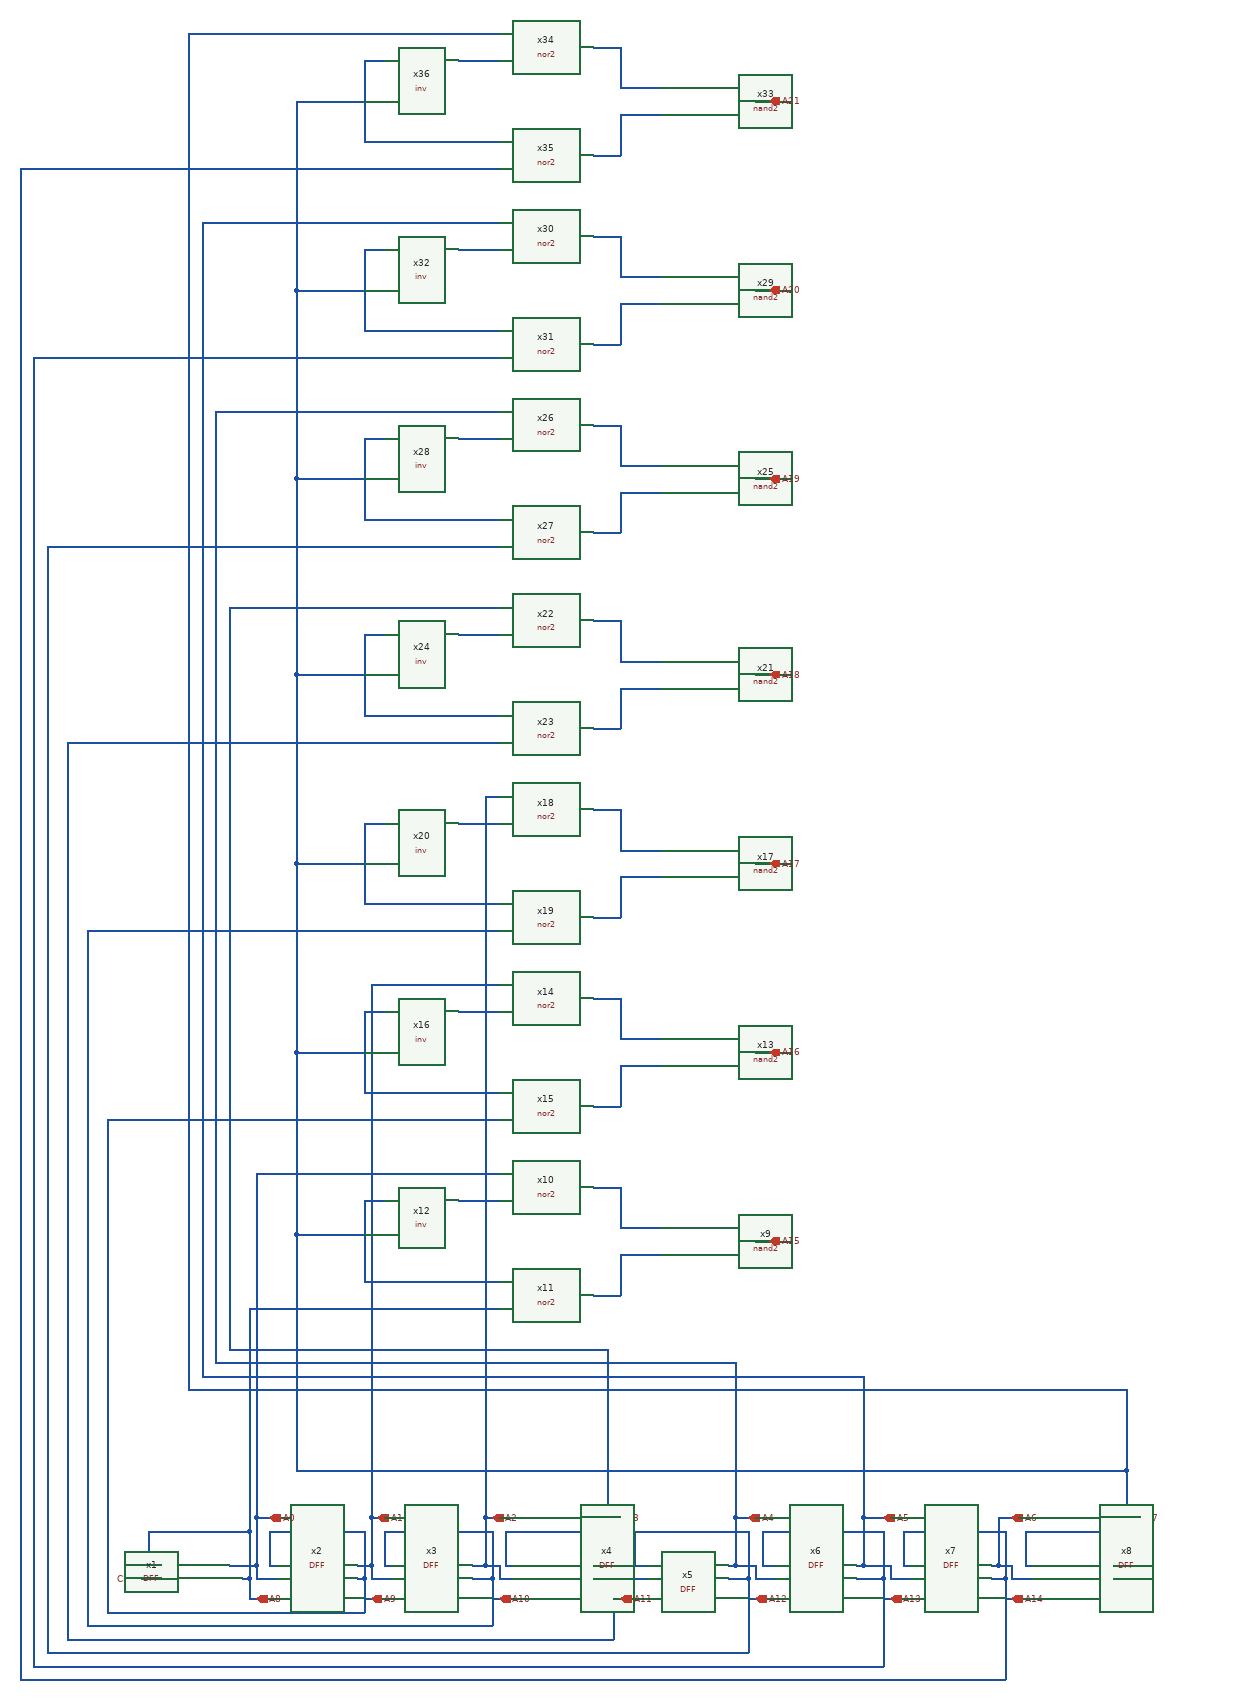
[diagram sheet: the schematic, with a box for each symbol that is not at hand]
v {xschem version=3.1.0 file_version=1.2 }
G {}
K {}
V {}
S {}
E {}
N 20 40 60 40 {
lab=A0}
N 60 -30 60 40 {
lab=A0}
N -80 -10 50 -10 {
lab=A8}
N 40 60 50 60 {
lab=A8}
N -100 40 -80 40 {
lab=A8}
N -100 -10 -100 40 {
lab=A8}
N -100 -10 -80 -10 {
lab=A8}
N 50 -10 50 60 {
lab=A8}
N 60 60 70 60 {
lab=A0}
N 60 40 60 60 {
lab=A0}
N 60 -30 90 -30 {
lab=A0}
N 70 60 90 60 {
lab=A0}
N 210 60 220 60 {
lab=A9}
N 220 -10 220 60 {
lab=A9}
N 80 -10 220 -10 {
lab=A9}
N 80 -10 80 40 {
lab=A9}
N 80 40 90 40 {
lab=A9}
N 210 40 230 40 {
lab=A1}
N 230 -30 230 40 {
lab=A1}
N 230 -30 250 -30 {
lab=A1}
N 230 40 230 60 {
lab=A1}
N 230 60 260 60 {
lab=A1}
N 250 40 260 40 {
lab=A10}
N 250 -10 250 40 {
lab=A10}
N 250 -10 410 -10 {
lab=A10}
N 410 -10 410 60 {
lab=A10}
N 380 60 410 60 {
lab=A10}
N 380 40 400 40 {
lab=A2}
N 400 -30 400 40 {
lab=A2}
N 400 -30 420 -30 {
lab=A2}
N 400 40 420 40 {
lab=A2}
N 420 40 420 60 {
lab=A2}
N 420 60 440 60 {
lab=A2}
N 430 40 440 40 {
lab=A11}
N 430 -10 430 40 {
lab=A11}
N 430 -10 590 -10 {
lab=A11}
N 590 -10 590 60 {
lab=A11}
N 560 60 590 60 {
lab=A11}
N 560 40 580 40 {
lab=A3}
N 580 -30 580 40 {
lab=A3}
N 580 -30 600 -30 {
lab=A3}
N 580 40 600 40 {
lab=A3}
N 600 40 600 60 {
lab=A3}
N 600 60 640 60 {
lab=A3}
N 620 40 640 40 {
lab=A12}
N 620 -10 620 40 {
lab=A12}
N 620 -10 790 -10 {
lab=A12}
N 790 -10 790 60 {
lab=A12}
N 760 60 790 60 {
lab=A12}
N 760 40 770 40 {
lab=A4}
N 770 -30 770 40 {
lab=A4}
N 770 -30 800 -30 {
lab=A4}
N 770 40 800 40 {
lab=A4}
N 800 40 800 60 {
lab=A4}
N 800 60 830 60 {
lab=A4}
N 810 40 830 40 {
lab=A13}
N 810 -10 810 40 {
lab=A13}
N 810 -10 990 -10 {
lab=A13}
N 990 -10 990 60 {
lab=A13}
N 950 60 990 60 {
lab=A13}
N 950 40 960 40 {
lab=A5}
N 960 -30 960 40 {
lab=A5}
N 960 -30 1000 -30 {
lab=A5}
N 960 40 1000 40 {
lab=A5}
N 1000 40 1000 60 {
lab=A5}
N 1000 60 1030 60 {
lab=A5}
N 1020 40 1030 40 {
lab=A14}
N 1020 -10 1020 40 {
lab=A14}
N 1020 -10 1170 -10 {
lab=A14}
N 1170 -10 1170 60 {
lab=A14}
N 1150 60 1170 60 {
lab=A14}
N 1150 40 1160 40 {
lab=A6}
N 1160 -30 1160 40 {
lab=A6}
N 1160 -30 1190 -30 {
lab=A6}
N 1160 40 1180 40 {
lab=A6}
N 1180 40 1180 60 {
lab=A6}
N 1180 60 1210 60 {
lab=A6}
N 1200 40 1210 40 {
lab=#net1}
N 1200 -10 1200 40 {
lab=#net1}
N 1200 -10 1360 -10 {
lab=#net1}
N 1360 -10 1360 60 {
lab=#net1}
N 1330 60 1360 60 {
lab=#net1}
N 1330 40 1350 40 {
lab=A7}
N 1350 -30 1350 40 {
lab=A7}
N 1350 -30 1370 -30 {
lab=A7}
N -110 60 -80 60 {
lab=CLK}
N 360 -500 420 -500 {
lab=#net2}
N 560 -520 600 -520 {
lab=#net3}
N 600 -520 600 -460 {
lab=#net3}
N 600 -460 660 -460 {
lab=#net3}
N 560 -360 600 -360 {
lab=#net4}
N 600 -420 600 -360 {
lab=#net4}
N 600 -420 660 -420 {
lab=#net4}
N 220 -380 420 -380 {
lab=A7}
N 220 -500 220 -380 {
lab=A7}
N 220 -500 250 -500 {
lab=A7}
N 340 -340 420 -340 {
lab=A8}
N 360 -540 420 -540 {
lab=A0}
N 120 -450 220 -450 {
lab=A7}
N 120 -450 120 -100 {
lab=A7}
N 120 -100 1350 -100 {
lab=A7}
N 1350 -100 1350 -30 {
lab=A7}
N 360 -780 420 -780 {
lab=#net5}
N 560 -800 600 -800 {
lab=#net6}
N 600 -800 600 -740 {
lab=#net6}
N 600 -740 660 -740 {
lab=#net6}
N 560 -640 600 -640 {
lab=#net7}
N 600 -700 600 -640 {
lab=#net7}
N 600 -700 660 -700 {
lab=#net7}
N 220 -660 420 -660 {
lab=#net8}
N 220 -780 220 -660 {
lab=#net8}
N 220 -780 250 -780 {
lab=#net8}
N 340 -620 420 -620 {
lab=A9}
N 360 -820 420 -820 {
lab=A1}
N 360 -1060 420 -1060 {
lab=#net9}
N 560 -1080 600 -1080 {
lab=#net10}
N 600 -1080 600 -1020 {
lab=#net10}
N 600 -1020 660 -1020 {
lab=#net10}
N 560 -920 600 -920 {
lab=#net11}
N 600 -980 600 -920 {
lab=#net11}
N 600 -980 660 -980 {
lab=#net11}
N 220 -940 420 -940 {
lab=#net12}
N 220 -1060 220 -940 {
lab=#net12}
N 220 -1060 250 -1060 {
lab=#net12}
N 340 -900 420 -900 {
lab=A10}
N 360 -1340 420 -1340 {
lab=#net13}
N 560 -1360 600 -1360 {
lab=#net14}
N 600 -1360 600 -1300 {
lab=#net14}
N 600 -1300 660 -1300 {
lab=#net14}
N 560 -1200 600 -1200 {
lab=#net15}
N 600 -1260 600 -1200 {
lab=#net15}
N 600 -1260 660 -1260 {
lab=#net15}
N 220 -1220 420 -1220 {
lab=#net16}
N 220 -1340 220 -1220 {
lab=#net16}
N 220 -1340 250 -1340 {
lab=#net16}
N 340 -1180 420 -1180 {
lab=A11}
N 360 -1380 420 -1380 {
lab=A3}
N 360 -1630 420 -1630 {
lab=#net17}
N 560 -1650 600 -1650 {
lab=#net18}
N 600 -1650 600 -1590 {
lab=#net18}
N 600 -1590 660 -1590 {
lab=#net18}
N 560 -1490 600 -1490 {
lab=#net19}
N 600 -1550 600 -1490 {
lab=#net19}
N 600 -1550 660 -1550 {
lab=#net19}
N 220 -1510 420 -1510 {
lab=#net20}
N 220 -1630 220 -1510 {
lab=#net20}
N 220 -1630 250 -1630 {
lab=#net20}
N 340 -1470 420 -1470 {
lab=A12}
N 360 -1670 420 -1670 {
lab=A4}
N 360 -1910 420 -1910 {
lab=#net21}
N 560 -1930 600 -1930 {
lab=#net22}
N 600 -1930 600 -1870 {
lab=#net22}
N 600 -1870 660 -1870 {
lab=#net22}
N 560 -1770 600 -1770 {
lab=#net23}
N 600 -1830 600 -1770 {
lab=#net23}
N 600 -1830 660 -1830 {
lab=#net23}
N 220 -1790 420 -1790 {
lab=#net24}
N 220 -1910 220 -1790 {
lab=#net24}
N 220 -1910 250 -1910 {
lab=#net24}
N 340 -1750 420 -1750 {
lab=A13}
N 360 -1950 420 -1950 {
lab=A5}
N 360 -2190 420 -2190 {
lab=#net25}
N 560 -2210 600 -2210 {
lab=#net26}
N 600 -2210 600 -2150 {
lab=#net26}
N 600 -2150 660 -2150 {
lab=#net26}
N 560 -2050 600 -2050 {
lab=#net27}
N 600 -2110 600 -2050 {
lab=#net27}
N 600 -2110 660 -2110 {
lab=#net27}
N 220 -2070 420 -2070 {
lab=#net28}
N 220 -2190 220 -2070 {
lab=#net28}
N 220 -2190 250 -2190 {
lab=#net28}
N 340 -2030 420 -2030 {
lab=A14}
N 360 -2230 420 -2230 {
lab=A7}
N 50 -340 50 -10 {
lab=A8}
N 50 -340 340 -340 {
lab=A8}
N 220 60 220 110 {
lab=A9}
N -160 110 220 110 {
lab=A9}
N -160 -620 -160 110 {
lab=A9}
N -160 -620 340 -620 {
lab=A9}
N 410 60 410 130 {
lab=A10}
N -190 130 410 130 {
lab=A10}
N -190 -900 -190 130 {
lab=A10}
N -190 -900 340 -900 {
lab=A10}
N 590 60 590 140 {
lab=A11}
N 590 140 590 150 {
lab=A11}
N -220 150 590 150 {
lab=A11}
N -220 -1180 -220 150 {
lab=A11}
N -220 -1180 340 -1180 {
lab=A11}
N 790 60 790 170 {
lab=A12}
N -250 170 790 170 {
lab=A12}
N -250 -1470 -250 170 {
lab=A12}
N -250 -1470 340 -1470 {
lab=A12}
N 990 60 990 190 {
lab=A13}
N -270 190 990 190 {
lab=A13}
N -270 -1750 -270 190 {
lab=A13}
N -270 -1750 340 -1750 {
lab=A13}
N 1170 60 1170 210 {
lab=A14}
N -290 210 1170 210 {
lab=A14}
N -290 -2030 -290 210 {
lab=A14}
N -290 -2030 340 -2030 {
lab=A14}
N 60 -140 60 -30 {
lab=A0}
N 60 -540 60 -140 {
lab=A0}
N 60 -540 360 -540 {
lab=A0}
N 230 -820 230 -30 {
lab=A1}
N 230 -820 360 -820 {
lab=A1}
N 400 -1100 400 -30 {
lab=A2}
N 400 -1100 420 -1100 {
lab=A2}
N 580 -280 580 -30 {
lab=A3}
N 20 -280 580 -280 {
lab=A3}
N 20 -1380 20 -280 {
lab=A3}
N 20 -1380 360 -1380 {
lab=A3}
N 770 -260 770 -30 {
lab=A4}
N 0 -260 770 -260 {
lab=A4}
N 0 -1670 0 -260 {
lab=A4}
N 0 -1670 360 -1670 {
lab=A4}
N 960 -240 960 -30 {
lab=A5}
N -20 -240 960 -240 {
lab=A5}
N -20 -1950 -20 -240 {
lab=A5}
N -20 -1950 360 -1950 {
lab=A5}
N 1350 -220 1350 -100 {
lab=A7}
N -40 -220 1350 -220 {
lab=A7}
N -40 -2230 -40 -220 {
lab=A7}
N -40 -2230 360 -2230 {
lab=A7}
N 50 60 50 90 {
lab=A8}
N 50 90 70 90 {
lab=A8}
N 220 90 240 90 {
lab=A9}
N 410 90 430 90 {
lab=A10}
N 590 90 610 90 {
lab=A11}
N 790 90 810 90 {
lab=A12}
N 990 90 1010 90 {
lab=A13}
N 1170 90 1190 90 {
lab=A14}
N 800 -2130 830 -2130 {
lab=A0}
N 800 -1850 830 -1850 {
lab=A20}
N 800 -1570 830 -1570 {
lab=A19}
N 800 -1280 830 -1280 {
lab=A18}
N 800 -1000 830 -1000 {
lab=A17}
N 800 -720 830 -720 {
lab=A16}
N 800 -440 830 -440 {
lab=A15}
N 120 -720 120 -450 {}
N 120 -720 220 -720 {}
N 120 -1000 120 -720 {}
N 120 -1000 220 -1000 {}
N 120 -1280 120 -1000 {}
N 120 -1280 220 -1280 {}
N 120 -1570 120 -1280 {}
N 120 -1570 220 -1570 {}
N 120 -1850 120 -1570 {}
N 120 -1850 220 -1850 {}
N 120 -2130 120 -1850 {}
N 120 -2130 220 -2130 {}
C {devices/ipin.sym} -100 60 0 0 {name=p1 lab=CLK}
C {DFF.sym} -20 50 0 0 {name=x1}
C {DFF.sym} 150 50 0 0 {name=x2}
C {devices/opin.sym} 1360 -30 0 0 {name=p1 lab=A7}
C {devices/opin.sym} 80 -30 0 0 {name=p1 lab=A0}
C {devices/opin.sym} 240 -30 0 0 {name=p1 lab=A1}
C {devices/opin.sym} 410 -30 0 0 {name=p1 lab=A2}
C {devices/opin.sym} 590 -30 0 0 {name=p1 lab=A3}
C {devices/opin.sym} 790 -30 0 0 {name=p1 lab=A4}
C {devices/opin.sym} 990 -30 0 0 {name=p1 lab=A5}
C {devices/opin.sym} 1180 -30 0 0 {name=p1 lab=A6}
C {DFF.sym} 320 50 0 0 {name=x3}
C {DFF.sym} 500 50 0 0 {name=x4}
C {DFF.sym} 700 50 0 0 {name=x5}
C {DFF.sym} 890 50 0 0 {name=x6}
C {DFF.sym} 1090 50 0 0 {name=x7}
C {DFF.sym} 1270 50 0 0 {name=x8}
C {nand2.sym} 720 -440 0 0 {name=x9}
C {nor2.sym} 480 -520 0 0 {name=x10}
C {nor2.sym} 480 -360 0 0 {name=x11}
C {inv.sym} 290 -500 0 0 {name=x12}
C {nand2.sym} 720 -720 0 0 {name=x13}
C {nor2.sym} 480 -800 0 0 {name=x14}
C {nor2.sym} 480 -640 0 0 {name=x15}
C {inv.sym} 290 -780 0 0 {name=x16}
C {nand2.sym} 720 -1000 0 0 {name=x17}
C {nor2.sym} 480 -1080 0 0 {name=x18}
C {nor2.sym} 480 -920 0 0 {name=x19}
C {inv.sym} 290 -1060 0 0 {name=x20}
C {nand2.sym} 720 -1280 0 0 {name=x21}
C {nor2.sym} 480 -1360 0 0 {name=x22}
C {nor2.sym} 480 -1200 0 0 {name=x23}
C {inv.sym} 290 -1340 0 0 {name=x24}
C {nand2.sym} 720 -1570 0 0 {name=x25}
C {nor2.sym} 480 -1650 0 0 {name=x26}
C {nor2.sym} 480 -1490 0 0 {name=x27}
C {inv.sym} 290 -1630 0 0 {name=x28}
C {nand2.sym} 720 -1850 0 0 {name=x29}
C {nor2.sym} 480 -1930 0 0 {name=x30}
C {nor2.sym} 480 -1770 0 0 {name=x31}
C {inv.sym} 290 -1910 0 0 {name=x32}
C {nand2.sym} 720 -2130 0 0 {name=x33}
C {nor2.sym} 480 -2210 0 0 {name=x34}
C {nor2.sym} 480 -2050 0 0 {name=x35}
C {inv.sym} 290 -2190 0 0 {name=x36}
C {devices/opin.sym} 60 90 0 0 {name=p1 lab=A8}
C {devices/opin.sym} 230 90 0 0 {name=p1 lab=A9}
C {devices/opin.sym} 420 90 0 0 {name=p1 lab=A10}
C {devices/opin.sym} 600 90 0 0 {name=p1 lab=A11}
C {devices/opin.sym} 800 90 0 0 {name=p1 lab=A12}
C {devices/opin.sym} 1000 90 0 0 {name=p1 lab=A13}
C {devices/opin.sym} 1180 90 0 0 {name=p1 lab=A14}
C {devices/opin.sym} 820 -440 0 0 {name=p1 lab=A15}
C {devices/opin.sym} 820 -720 0 0 {name=p1 lab=A16}
C {devices/opin.sym} 820 -1000 0 0 {name=p1 lab=A17}
C {devices/opin.sym} 820 -1280 0 0 {name=p1 lab=A18}
C {devices/opin.sym} 820 -1570 0 0 {name=p1 lab=A19}
C {devices/opin.sym} 820 -1850 0 0 {name=p1 lab=A20}
C {devices/opin.sym} 820 -2130 0 0 {name=p1 lab=A21}
